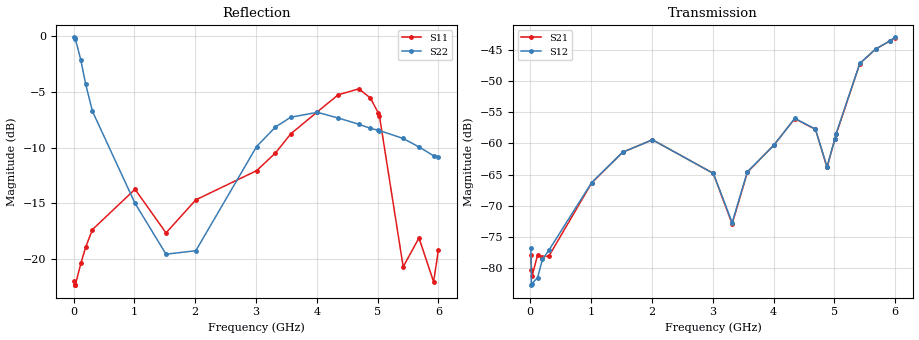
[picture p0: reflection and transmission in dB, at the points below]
!Agilent Technologies,N5230A,MY45001650,A.07.50.48
!Agilent N5230A: A.07.50.48
!Date: Saturday, July 08, 2017 15:59:33
!Correction: S11(Full 2 Port(1,2))
!S21(Full 2 Port(1,2))
!S12(Full 2 Port(1,2))
!S22(Full 2 Port(1,2))
!S2P File: Measurements: S11, S21, S12, S22:
# Hz S  dB  R 50
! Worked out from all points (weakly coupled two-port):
!   600 points, 10 MHz to 6 GHz, reference 50 ohm
!   highest |S21| = -43.00 dB at 6 GHz (marker M1); lowest = -81.3 dB at 30 MHz (marker M2)
!   lowest |S11| = -22.4 dB at 20 MHz (marker M3), VSWR 1.16, Z = 58.1 - j1.45 ohm
!   |S11| at or under -10 dB: start of sweep to 3.385 GHz; 5.159 GHz to end of sweep
!   |S22| runs from -20.7 to -0.1 dB; largest |S21 - S12| = 0.00027
!   S11 on the Smith chart (normalised r, x): 10 MHz: 1.17, -0.03; 1.52 GHz: 0.78, +0.06; 3.57 GHz: 0.75, +0.63; 4.35 GHz: 2.95, +1.09; 5.03 GHz: 1.37, -1.08; 6 GHz: 1.07, +0.22
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1e7  -21.96 -7.9  -77.85 67.5  -76.85 -123.0  -0.11 -5.7
2e7  -22.36 -9.4  -80.25 98.5  -82.75 142.1  -0.15 -11.0
3e7  -22.32 -13.0  -81.30 92.3  -82.49 89.2  -0.26 -16.4
1.2e8  -20.39 -42.6  -77.93 64.0  -81.55 48.2  -2.17 -56.3
2e8  -18.93 -65.5  -78.25 49.1  -78.63 52.4  -4.34 -80.9
3.1e8  -17.37 -92.6  -78.03 51.5  -77.09 54.1  -6.75 -104.2
1.01e9  -13.75 177.4  -66.34 65.5  -66.28 65.0  -15.01 -165.5
1.52e9  -17.67 163.8  -61.41 37.0  -61.40 37.2  -19.58 -178.3
2.01e9  -14.70 167.9  -59.41 6.6  -59.42 6.6  -19.27 -174.9
3.01e9  -12.08 138.6  -64.81 -78.5  -64.80 -78.2  -9.91 152.7
3.32e9  -10.49 120.8  -72.93 163.9  -72.71 165.9  -8.16 142.3
3.57e9  -8.78 91.3  -64.65 68.0  -64.55 66.6  -7.28 134.8
4.01e9  -6.79 40.1  -60.21 26.0  -60.25 25.5  -6.84 119.0
4.35e9  -5.27 13.7  -56.02 1.3  -55.96 1.0  -7.35 105.8
4.69e9  -4.73 -14.3  -57.74 -37.3  -57.72 -36.9  -7.91 88.6
4.88e9  -5.55 -31.9  -63.85 -18.6  -63.75 -19.4  -8.28 77.5
5.01e9  -6.89 -44.5  -59.30 16.4  -59.21 16.7  -8.45 69.8
5.03e9  -7.18 -46.5  -58.54 18.6  -58.43 18.4  -8.48 68.0
5.42e9  -20.71 -35.4  -47.17 -9.8  -47.13 -9.9  -9.19 43.7
5.68e9  -18.12 4.1  -44.85 -44.3  -44.83 -44.3  -9.95 27.3
5.92e9  -22.07 46.9  -43.51 -66.6  -43.50 -66.6  -10.74 14.1
6e9  -19.17 65.1  -43.00 -73.6  -42.97 -73.5  -10.83 9.3
